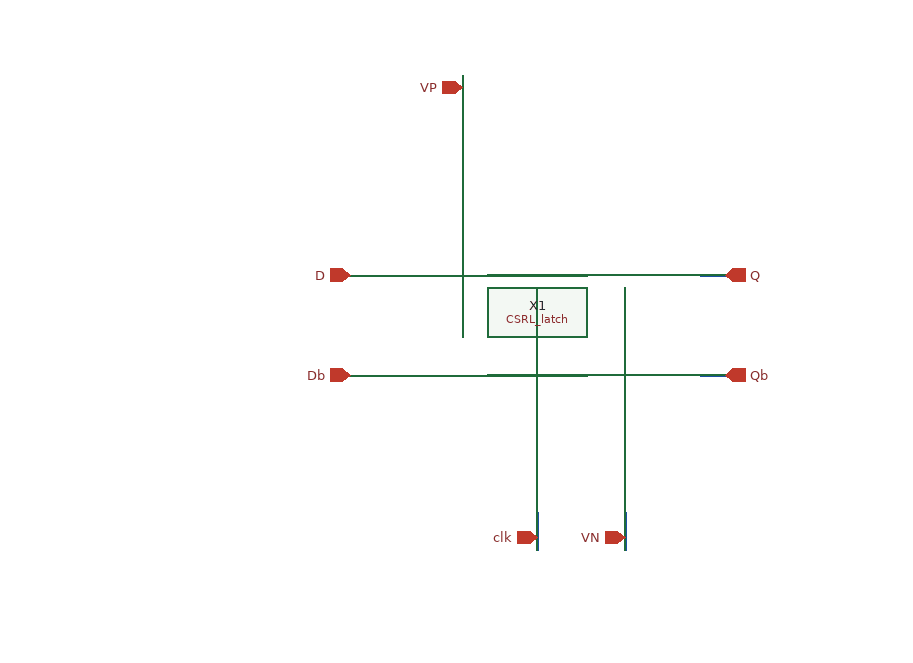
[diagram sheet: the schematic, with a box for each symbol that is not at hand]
v {xschem version=2.9.9 file_version=1.2 }
G {}
K {}
V {}
S {}
E {}
N 130 -280 160 -280 { lab=D}
N 130 -200 160 -200 { lab=Db}
N 290 -90 290 -60 { lab=clk}
N 360 -90 360 -60 { lab=VN}
N 420 -200 450 -200 { lab=Qb}
N 420 -280 450 -280 { lab=Q}
N 230 -440 230 -410 { lab=VP}
C {/home/madvlsi/Documents/Mini_Project_2/CSRL_latch.sym} -50 -40 0 0 {name=X1}
C {devices/ipin.sym} 140 -280 0 0 {name=p1 lab=D}
C {devices/ipin.sym} 140 -200 0 0 {name=p2 lab=Db}
C {devices/opin.sym} 440 -280 0 0 {name=p3 lab=Q}
C {devices/opin.sym} 440 -200 0 0 {name=p5 lab=Qb}
C {devices/iopin.sym} 290 -70 1 0 {name=p6 lab=clk}
C {devices/iopin.sym} 230 -430 3 0 {name=p7 lab=VP}
C {devices/iopin.sym} 360 -70 1 0 {name=p8 lab=VN}
